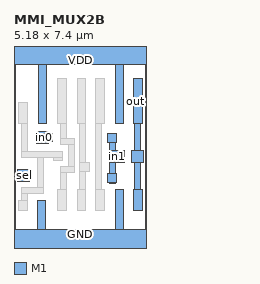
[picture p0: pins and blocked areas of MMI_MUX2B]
MACRO MMI_MUX2B
	CLASS CORE ;
	FOREIGN MMI_MUX2B 0 0 ;
	SIZE 5.18 BY 7.4 ;
	SYMMETRY X Y ;
	SITE CORE1 ;
	PIN out
		DIRECTION output ;
		USE SIGNAL ;
		PORT
			LAYER M1 ;
			RECT 4.66 4.61 5 6.37 ;
			LAYER M1 ;
			RECT 4.71 3.555 4.94 4.61 ;
			LAYER M1 ;
			RECT 4.585 3.105 5.035 3.555 ;
			LAYER M1 ;
			RECT 4.71 2.06 4.94 3.105 ;
			LAYER M1 ;
			RECT 4.66 1.22 5 2.06 ;
		END
		AntennaDiffArea 1.3248 ;
	END out
	PIN sel
		DIRECTION input ;
		USE SIGNAL ;
		PORT
			LAYER M1 ;
			RECT 0.145 2.365 0.595 2.815 ;
		END
		AntennaGateArea 0.7452 ;
	END sel
	PIN in1
		DIRECTION input ;
		USE SIGNAL ;
		PORT
			LAYER M1 ;
			RECT 3.65 3.885 3.99 4.225 ;
			LAYER M1 ;
			RECT 3.715 3.555 3.945 3.885 ;
			LAYER M1 ;
			RECT 3.715 3.105 4.295 3.555 ;
			LAYER M1 ;
			RECT 3.715 2.66 3.945 3.105 ;
			LAYER M1 ;
			RECT 3.66 2.32 4 2.66 ;
			LAYER M1 ;
			RECT 3.715 2.295 3.945 2.32 ;
		END
		AntennaGateArea 0.4968 ;
	END in1
	PIN GND
		DIRECTION inout ;
		USE GROUND ;
		PORT
			LAYER M1 ;
			RECT 0.9 0.5 1.24 1.6 ;
			LAYER M1 ;
			RECT 3.94 0.5 4.28 2.06 ;
			LAYER M1 ;
			RECT 0 -0.5 5.18 0.5 ;
		END
	END GND
	PIN VDD
		DIRECTION inout ;
		USE POWER ;
		PORT
			LAYER M1 ;
			RECT 0 6.9 5.18 7.9 ;
			LAYER M1 ;
			RECT 0.94 4.61 1.28 6.9 ;
			LAYER M1 ;
			RECT 3.94 4.61 4.28 6.9 ;
		END
	END VDD
	PIN in0
		DIRECTION input ;
		USE SIGNAL ;
		PORT
			LAYER M1 ;
			RECT 0.885 4.245 1.335 4.295 ;
			LAYER M1 ;
			RECT 0.885 3.905 1.48 4.245 ;
			LAYER M1 ;
			RECT 0.885 3.845 1.335 3.905 ;
		END
		AntennaGateArea 0.4968 ;
	END in0
	OBS
		LAYER M1 ;
		RECT 0.18 4.61 0.52 5.45 ;
		LAYER M1 ;
		RECT 1.7 4.61 2.04 6.37 ;
		LAYER M1 ;
		RECT 2.46 4.61 2.8 6.37 ;
		LAYER M1 ;
		RECT 3.18 4.61 3.52 6.37 ;
		LAYER M1 ;
		RECT 0.29 3.525 0.52 4.61 ;
		LAYER M1 ;
		RECT 1.81 4.02 2.04 4.61 ;
		LAYER M1 ;
		RECT 1.81 3.79 2.34 4.02 ;
		LAYER M1 ;
		RECT 0.29 3.295 1.88 3.525 ;
		LAYER M1 ;
		RECT 0.925 2.135 1.155 3.295 ;
		LAYER M1 ;
		RECT 1.54 3.185 1.88 3.295 ;
		LAYER M1 ;
		RECT 2.11 2.955 2.34 3.79 ;
		LAYER M1 ;
		RECT 0.29 1.905 1.155 2.135 ;
		LAYER M1 ;
		RECT 1.81 2.725 2.34 2.955 ;
		LAYER M1 ;
		RECT 2.57 3.095 2.8 4.61 ;
		LAYER M1 ;
		RECT 2.57 2.755 2.95 3.095 ;
		LAYER M1 ;
		RECT 1.81 2.06 2.04 2.725 ;
		LAYER M1 ;
		RECT 2.57 2.06 2.8 2.755 ;
		LAYER M1 ;
		RECT 3.19 2.06 3.42 4.61 ;
		LAYER M1 ;
		RECT 0.29 1.6 0.52 1.905 ;
		LAYER M1 ;
		RECT 0.18 1.22 0.52 1.6 ;
		LAYER M1 ;
		RECT 1.7 1.22 2.04 2.06 ;
		LAYER M1 ;
		RECT 2.46 1.22 2.8 2.06 ;
		LAYER M1 ;
		RECT 3.18 1.22 3.52 2.06 ;
	END
END MMI_MUX2B
